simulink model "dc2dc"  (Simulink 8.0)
settings: Solver=ode45  StartTime=0.0  StopTime=0.001  RelTol=1e-3
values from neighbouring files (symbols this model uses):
  a00c = sys(1).Ac(1,1)    [matrices.m]
  a00o = sys(1).Ao(1,1)    [matrices.m]
  a01c = sys(1).Ac(1,2)    [matrices.m]
  a01o = sys(1).Ao(1,2)    [matrices.m]
  a10c = sys(1).Ac(2,1)    [matrices.m]
  a10o = sys(1).Ao(2,1)    [matrices.m]
  a11c = sys(1).Ac(2,2)    [matrices.m]
  a11o = sys(1).Ao(2,2)    [matrices.m]
  b0c = sys(1).Bc(1)    [matrices.m]
  b0o = sys(1).Bo(1)    [matrices.m]
  b1c = sys(1).Bc(2)    [matrices.m]
  b1o = sys(1).Bo(2)    [matrices.m]
  D = Vref/(Vref + Vs)    (= 0.428571428571)    [matrices.m]
  i0 = 6    [matrices.m]
  T = 4e-6    (= 4e-06)    [matrices.m]
  v0 = 17.5    [matrices.m]
  Vs = 20    [matrices.m]
  Vs_noise = 0.1    [matrices.m]

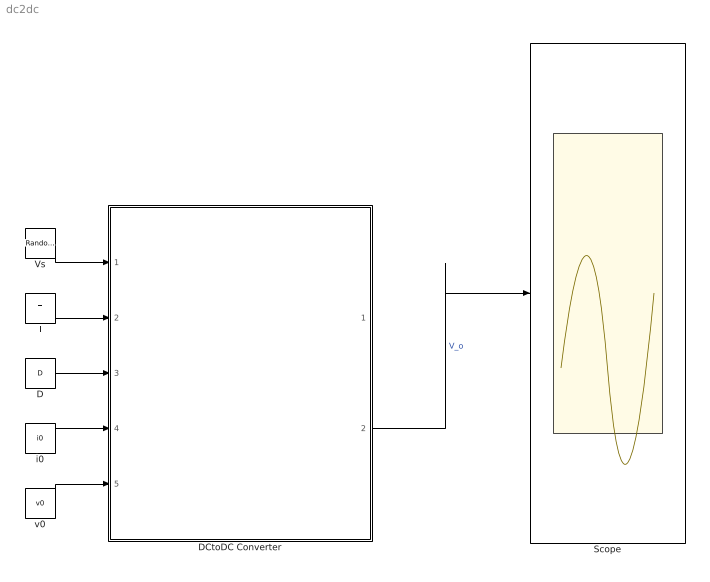
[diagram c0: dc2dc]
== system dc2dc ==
  D : Constant  Value=D
  DCtoDC Converter : Stateflow chart  TreatAsAtomicUnit=on
  Scope : Scope
  T : Constant  Value=T
  Vs : RandomNumber  Mean=Vs  Variance=Vs_noise  SampleTime=T/10
  i0 : Constant  Value=i0
  v0 : Constant  Value=v0
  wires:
  D/1 -> DCtoDC Converter/3(D)
  T/1 -> DCtoDC Converter/2(T)
  Vs/1 -> DCtoDC Converter/1(Vs)
  i0/1 -> DCtoDC Converter/4(i0)
  v0/1 -> DCtoDC Converter/5(v0)
  DCtoDC Converter/2(v_out) -> Scope/1  "V_o"

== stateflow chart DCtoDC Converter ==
  state Charging
    du:
    i_dot = a00c*i+a01c*v+b0c*Vs;
    v_dot = a10c*i+a11c*v+b1c*Vs;
    t_dot = 1;
    i_out = i;
    v_out = v;
  state Discharging
    du:
    i_dot = a00o*i+a01o*v+b0o*Vs;
    v_dot = a10o*i+a11o*v+b1o*Vs;
    t_dot = 1;
    i_out = i;
    v_out = v;
  Charging -> Discharging : [t>= D*T] {t= 0;}
  Discharging -> Charging : [t>= (1-D)*T] {t= 0;}
  (default) -> Discharging : {i = i0; v = v0;}
